VERSION 5.7 ;
  NOWIREEXTENSIONATPIN ON ;
  DIVIDERCHAR "/" ;
  BUSBITCHARS "[]" ;
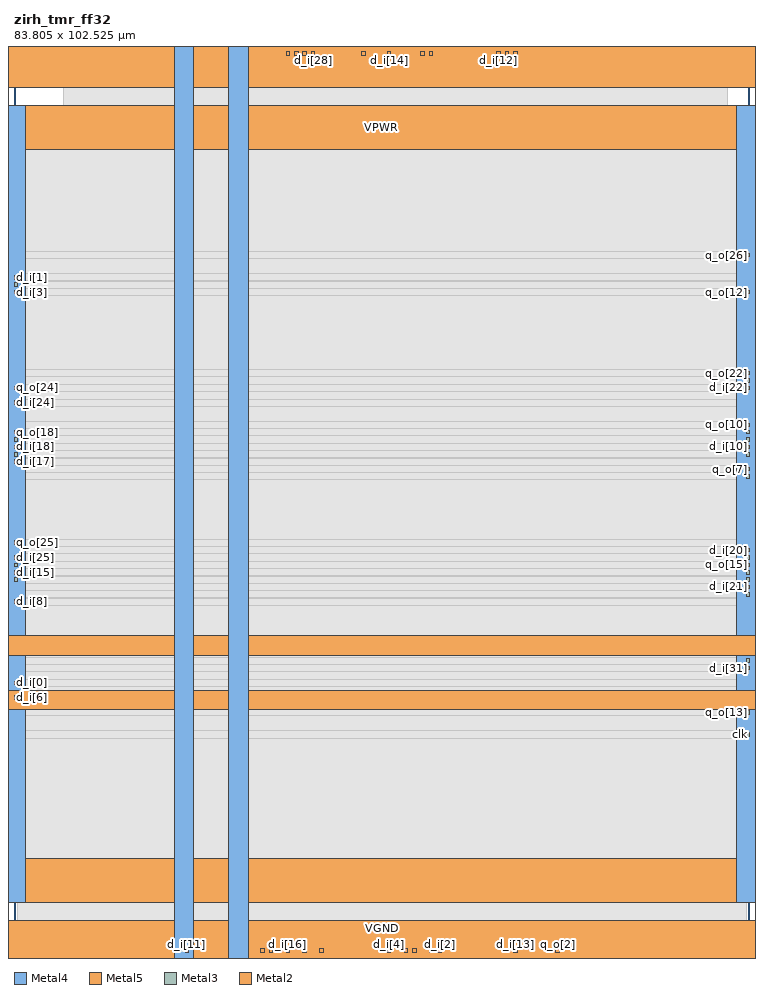
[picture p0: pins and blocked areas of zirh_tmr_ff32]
MACRO zirh_tmr_ff32
  CLASS BLOCK ;
  FOREIGN zirh_tmr_ff32 ;
  ORIGIN 0.000 0.000 ;
  SIZE 83.805 BY 102.525 ;
  PIN VGND
    DIRECTION INOUT ;
    USE GROUND ;
    PORT
      LAYER Metal4 ;
        RECT -10.740 -1.380 -5.740 103.440 ;
    END
    PORT
      LAYER Metal4 ;
        RECT 89.260 -1.380 94.260 103.440 ;
    END
    PORT
      LAYER Metal5 ;
        RECT -10.740 -1.380 94.260 3.620 ;
    END
    PORT
      LAYER Metal5 ;
        RECT -10.740 98.440 94.260 103.440 ;
    END
    PORT
      LAYER Metal4 ;
        RECT 24.460 -1.380 26.660 103.440 ;
    END
    PORT
      LAYER Metal5 ;
        RECT -10.740 33.820 94.260 36.020 ;
    END
  END VGND
  PIN VPWR
    DIRECTION INOUT ;
    USE POWER ;
    PORT
      LAYER Metal4 ;
        RECT -3.740 5.620 1.260 96.440 ;
    END
    PORT
      LAYER Metal4 ;
        RECT 82.260 5.620 87.260 96.440 ;
    END
    PORT
      LAYER Metal5 ;
        RECT -3.740 5.620 87.260 10.620 ;
    END
    PORT
      LAYER Metal5 ;
        RECT -3.740 91.440 87.260 96.440 ;
    END
    PORT
      LAYER Metal4 ;
        RECT 18.260 -1.380 20.460 103.440 ;
    END
    PORT
      LAYER Metal5 ;
        RECT -10.740 27.620 94.260 29.820 ;
    END
  END VPWR
  PIN clk
    DIRECTION INPUT ;
    USE SIGNAL ;
    ANTENNAGATEAREA 1.450800 ;
    PORT
      LAYER Metal3 ;
        RECT 83.405 24.580 83.805 24.980 ;
    END
  END clk
  PIN d_i[0]
    DIRECTION INPUT ;
    USE SIGNAL ;
    ANTENNAGATEAREA 0.180700 ;
    PORT
      LAYER Metal3 ;
        RECT 0.000 30.460 0.400 30.860 ;
    END
  END d_i[0]
  PIN d_i[10]
    DIRECTION INPUT ;
    USE SIGNAL ;
    ANTENNAGATEAREA 0.180700 ;
    PORT
      LAYER Metal3 ;
        RECT 83.405 57.340 83.805 57.740 ;
    END
  END d_i[10]
  PIN d_i[11]
    DIRECTION INPUT ;
    USE SIGNAL ;
    ANTENNAGATEAREA 0.180700 ;
    PORT
      LAYER Metal2 ;
        RECT 19.480 0.000 19.880 0.400 ;
    END
  END d_i[11]
  PIN d_i[12]
    DIRECTION INPUT ;
    USE SIGNAL ;
    ANTENNAGATEAREA 0.180700 ;
    PORT
      LAYER Metal2 ;
        RECT 55.000 102.125 55.400 102.525 ;
    END
  END d_i[12]
  PIN d_i[13]
    DIRECTION INPUT ;
    USE SIGNAL ;
    ANTENNAGATEAREA 0.180700 ;
    PORT
      LAYER Metal2 ;
        RECT 56.920 0.000 57.320 0.400 ;
    END
  END d_i[13]
  PIN d_i[14]
    DIRECTION INPUT ;
    USE SIGNAL ;
    ANTENNAGATEAREA 0.180700 ;
    PORT
      LAYER Metal2 ;
        RECT 42.520 102.125 42.920 102.525 ;
    END
  END d_i[14]
  PIN d_i[15]
    DIRECTION INPUT ;
    USE SIGNAL ;
    ANTENNAGATEAREA 0.180700 ;
    PORT
      LAYER Metal3 ;
        RECT 0.000 43.060 0.400 43.460 ;
    END
  END d_i[15]
  PIN d_i[16]
    DIRECTION INPUT ;
    USE SIGNAL ;
    ANTENNAGATEAREA 0.180700 ;
    PORT
      LAYER Metal2 ;
        RECT 31.000 0.000 31.400 0.400 ;
    END
  END d_i[16]
  PIN d_i[17]
    DIRECTION INPUT ;
    USE SIGNAL ;
    ANTENNAGATEAREA 0.180700 ;
    PORT
      LAYER Metal3 ;
        RECT 0.000 55.660 0.400 56.060 ;
    END
  END d_i[17]
  PIN d_i[18]
    DIRECTION INPUT ;
    USE SIGNAL ;
    ANTENNAGATEAREA 0.180700 ;
    PORT
      LAYER Metal3 ;
        RECT 0.000 57.340 0.400 57.740 ;
    END
  END d_i[18]
  PIN d_i[19]
    DIRECTION INPUT ;
    USE SIGNAL ;
    ANTENNAGATEAREA 0.180700 ;
    PORT
      LAYER Metal2 ;
        RECT 34.840 0.000 35.240 0.400 ;
    END
  END d_i[19]
  PIN d_i[1]
    DIRECTION INPUT ;
    USE SIGNAL ;
    ANTENNAGATEAREA 0.180700 ;
    PORT
      LAYER Metal3 ;
        RECT 0.000 76.660 0.400 77.060 ;
    END
  END d_i[1]
  PIN d_i[20]
    DIRECTION INPUT ;
    USE SIGNAL ;
    ANTENNAGATEAREA 0.180700 ;
    PORT
      LAYER Metal3 ;
        RECT 83.405 45.580 83.805 45.980 ;
    END
  END d_i[20]
  PIN d_i[21]
    DIRECTION INPUT ;
    USE SIGNAL ;
    ANTENNAGATEAREA 0.180700 ;
    PORT
      LAYER Metal3 ;
        RECT 83.405 41.380 83.805 41.780 ;
    END
  END d_i[21]
  PIN d_i[22]
    DIRECTION INPUT ;
    USE SIGNAL ;
    ANTENNAGATEAREA 0.180700 ;
    PORT
      LAYER Metal3 ;
        RECT 83.405 64.060 83.805 64.460 ;
    END
  END d_i[22]
  PIN d_i[23]
    DIRECTION INPUT ;
    USE SIGNAL ;
    ANTENNAGATEAREA 0.180700 ;
    PORT
      LAYER Metal2 ;
        RECT 39.640 102.125 40.040 102.525 ;
    END
  END d_i[23]
  PIN d_i[24]
    DIRECTION INPUT ;
    USE SIGNAL ;
    ANTENNAGATEAREA 0.180700 ;
    PORT
      LAYER Metal3 ;
        RECT 0.000 62.380 0.400 62.780 ;
    END
  END d_i[24]
  PIN d_i[25]
    DIRECTION INPUT ;
    USE SIGNAL ;
    ANTENNAGATEAREA 0.180700 ;
    PORT
      LAYER Metal3 ;
        RECT 0.000 44.740 0.400 45.140 ;
    END
  END d_i[25]
  PIN d_i[26]
    DIRECTION INPUT ;
    USE SIGNAL ;
    ANTENNAGATEAREA 0.180700 ;
    PORT
      LAYER Metal2 ;
        RECT 55.960 102.125 56.360 102.525 ;
    END
  END d_i[26]
  PIN d_i[27]
    DIRECTION INPUT ;
    USE SIGNAL ;
    ANTENNAGATEAREA 0.180700 ;
    PORT
      LAYER Metal3 ;
        RECT 0.000 42.220 0.400 42.620 ;
    END
  END d_i[27]
  PIN d_i[28]
    DIRECTION INPUT ;
    USE SIGNAL ;
    ANTENNAGATEAREA 0.180700 ;
    PORT
      LAYER Metal2 ;
        RECT 33.880 102.125 34.280 102.525 ;
    END
  END d_i[28]
  PIN d_i[29]
    DIRECTION INPUT ;
    USE SIGNAL ;
    ANTENNAGATEAREA 0.180700 ;
    PORT
      LAYER Metal3 ;
        RECT 0.000 56.500 0.400 56.900 ;
    END
  END d_i[29]
  PIN d_i[2]
    DIRECTION INPUT ;
    USE SIGNAL ;
    ANTENNAGATEAREA 0.180700 ;
    PORT
      LAYER Metal2 ;
        RECT 48.280 0.000 48.680 0.400 ;
    END
  END d_i[2]
  PIN d_i[30]
    DIRECTION INPUT ;
    USE SIGNAL ;
    ANTENNAGATEAREA 0.180700 ;
    PORT
      LAYER Metal3 ;
        RECT 83.405 40.540 83.805 40.940 ;
    END
  END d_i[30]
  PIN d_i[31]
    DIRECTION INPUT ;
    USE SIGNAL ;
    ANTENNAGATEAREA 0.180700 ;
    PORT
      LAYER Metal3 ;
        RECT 83.405 32.140 83.805 32.540 ;
    END
  END d_i[31]
  PIN d_i[3]
    DIRECTION INPUT ;
    USE SIGNAL ;
    ANTENNAGATEAREA 0.180700 ;
    PORT
      LAYER Metal3 ;
        RECT 0.000 74.980 0.400 75.380 ;
    END
  END d_i[3]
  PIN d_i[4]
    DIRECTION INPUT ;
    USE SIGNAL ;
    ANTENNAGATEAREA 0.180700 ;
    PORT
      LAYER Metal2 ;
        RECT 42.520 0.000 42.920 0.400 ;
    END
  END d_i[4]
  PIN d_i[5]
    DIRECTION INPUT ;
    USE SIGNAL ;
    ANTENNAGATEAREA 0.180700 ;
    PORT
      LAYER Metal3 ;
        RECT 83.405 56.500 83.805 56.900 ;
    END
  END d_i[5]
  PIN d_i[6]
    DIRECTION INPUT ;
    USE SIGNAL ;
    ANTENNAGATEAREA 0.180700 ;
    PORT
      LAYER Metal3 ;
        RECT 0.000 28.780 0.400 29.180 ;
    END
  END d_i[6]
  PIN d_i[7]
    DIRECTION INPUT ;
    USE SIGNAL ;
    ANTENNAGATEAREA 0.180700 ;
    PORT
      LAYER Metal3 ;
        RECT 83.405 53.980 83.805 54.380 ;
    END
  END d_i[7]
  PIN d_i[8]
    DIRECTION INPUT ;
    USE SIGNAL ;
    ANTENNAGATEAREA 0.180700 ;
    PORT
      LAYER Metal3 ;
        RECT 0.000 39.700 0.400 40.100 ;
    END
  END d_i[8]
  PIN d_i[9]
    DIRECTION INPUT ;
    USE SIGNAL ;
    ANTENNAGATEAREA 0.180700 ;
    PORT
      LAYER Metal2 ;
        RECT 32.920 102.125 33.320 102.525 ;
    END
  END d_i[9]
  PIN q_o[0]
    DIRECTION OUTPUT ;
    USE SIGNAL ;
    ANTENNADIFFAREA 0.708600 ;
    PORT
      LAYER Metal2 ;
        RECT 28.120 0.000 28.520 0.400 ;
    END
  END q_o[0]
  PIN q_o[10]
    DIRECTION OUTPUT ;
    USE SIGNAL ;
    ANTENNADIFFAREA 0.708600 ;
    PORT
      LAYER Metal3 ;
        RECT 83.405 59.860 83.805 60.260 ;
    END
  END q_o[10]
  PIN q_o[11]
    DIRECTION OUTPUT ;
    USE SIGNAL ;
    ANTENNADIFFAREA 0.708600 ;
    PORT
      LAYER Metal2 ;
        RECT 32.920 0.000 33.320 0.400 ;
    END
  END q_o[11]
  PIN q_o[12]
    DIRECTION OUTPUT ;
    USE SIGNAL ;
    ANTENNADIFFAREA 0.708600 ;
    PORT
      LAYER Metal3 ;
        RECT 83.405 74.980 83.805 75.380 ;
    END
  END q_o[12]
  PIN q_o[13]
    DIRECTION OUTPUT ;
    USE SIGNAL ;
    ANTENNADIFFAREA 0.708600 ;
    PORT
      LAYER Metal3 ;
        RECT 83.405 27.100 83.805 27.500 ;
    END
  END q_o[13]
  PIN q_o[14]
    DIRECTION OUTPUT ;
    USE SIGNAL ;
    ANTENNADIFFAREA 0.708600 ;
    PORT
      LAYER Metal2 ;
        RECT 56.920 102.125 57.320 102.525 ;
    END
  END q_o[14]
  PIN q_o[15]
    DIRECTION OUTPUT ;
    USE SIGNAL ;
    ANTENNADIFFAREA 0.708600 ;
    PORT
      LAYER Metal3 ;
        RECT 83.405 43.900 83.805 44.300 ;
    END
  END q_o[15]
  PIN q_o[16]
    DIRECTION OUTPUT ;
    USE SIGNAL ;
    ANTENNADIFFAREA 0.708600 ;
    PORT
      LAYER Metal2 ;
        RECT 45.400 0.000 45.800 0.400 ;
    END
  END q_o[16]
  PIN q_o[17]
    DIRECTION OUTPUT ;
    USE SIGNAL ;
    ANTENNADIFFAREA 0.708600 ;
    PORT
      LAYER Metal3 ;
        RECT 83.405 59.020 83.805 59.420 ;
    END
  END q_o[17]
  PIN q_o[18]
    DIRECTION OUTPUT ;
    USE SIGNAL ;
    ANTENNADIFFAREA 0.708600 ;
    PORT
      LAYER Metal3 ;
        RECT 0.000 59.020 0.400 59.420 ;
    END
  END q_o[18]
  PIN q_o[19]
    DIRECTION OUTPUT ;
    USE SIGNAL ;
    ANTENNADIFFAREA 0.708600 ;
    PORT
      LAYER Metal2 ;
        RECT 47.320 0.000 47.720 0.400 ;
    END
  END q_o[19]
  PIN q_o[1]
    DIRECTION OUTPUT ;
    USE SIGNAL ;
    ANTENNADIFFAREA 0.708600 ;
    PORT
      LAYER Metal2 ;
        RECT 31.960 102.125 32.360 102.525 ;
    END
  END q_o[1]
  PIN q_o[20]
    DIRECTION OUTPUT ;
    USE SIGNAL ;
    ANTENNADIFFAREA 0.708600 ;
    PORT
      LAYER Metal3 ;
        RECT 83.405 44.740 83.805 45.140 ;
    END
  END q_o[20]
  PIN q_o[21]
    DIRECTION OUTPUT ;
    USE SIGNAL ;
    ANTENNADIFFAREA 0.708600 ;
    PORT
      LAYER Metal3 ;
        RECT 83.405 43.060 83.805 43.460 ;
    END
  END q_o[21]
  PIN q_o[22]
    DIRECTION OUTPUT ;
    USE SIGNAL ;
    ANTENNADIFFAREA 0.708600 ;
    PORT
      LAYER Metal3 ;
        RECT 83.405 65.740 83.805 66.140 ;
    END
  END q_o[22]
  PIN q_o[23]
    DIRECTION OUTPUT ;
    USE SIGNAL ;
    ANTENNADIFFAREA 0.708600 ;
    PORT
      LAYER Metal3 ;
        RECT 83.405 64.900 83.805 65.300 ;
    END
  END q_o[23]
  PIN q_o[24]
    DIRECTION OUTPUT ;
    USE SIGNAL ;
    ANTENNADIFFAREA 0.708600 ;
    PORT
      LAYER Metal3 ;
        RECT 0.000 64.060 0.400 64.460 ;
    END
  END q_o[24]
  PIN q_o[25]
    DIRECTION OUTPUT ;
    USE SIGNAL ;
    ANTENNADIFFAREA 0.708600 ;
    PORT
      LAYER Metal3 ;
        RECT 0.000 46.420 0.400 46.820 ;
    END
  END q_o[25]
  PIN q_o[26]
    DIRECTION OUTPUT ;
    USE SIGNAL ;
    ANTENNADIFFAREA 0.708600 ;
    PORT
      LAYER Metal3 ;
        RECT 83.405 79.180 83.805 79.580 ;
    END
  END q_o[26]
  PIN q_o[27]
    DIRECTION OUTPUT ;
    USE SIGNAL ;
    ANTENNADIFFAREA 0.708600 ;
    PORT
      LAYER Metal3 ;
        RECT 0.000 43.900 0.400 44.300 ;
    END
  END q_o[27]
  PIN q_o[28]
    DIRECTION OUTPUT ;
    USE SIGNAL ;
    ANTENNADIFFAREA 0.708600 ;
    PORT
      LAYER Metal2 ;
        RECT 47.320 102.125 47.720 102.525 ;
    END
  END q_o[28]
  PIN q_o[29]
    DIRECTION OUTPUT ;
    USE SIGNAL ;
    ANTENNADIFFAREA 0.708600 ;
    PORT
      LAYER Metal3 ;
        RECT 0.000 58.180 0.400 58.580 ;
    END
  END q_o[29]
  PIN q_o[2]
    DIRECTION OUTPUT ;
    USE SIGNAL ;
    ANTENNADIFFAREA 0.708600 ;
    PORT
      LAYER Metal2 ;
        RECT 61.720 0.000 62.120 0.400 ;
    END
  END q_o[2]
  PIN q_o[30]
    DIRECTION OUTPUT ;
    USE SIGNAL ;
    ANTENNADIFFAREA 0.708600 ;
    PORT
      LAYER Metal3 ;
        RECT 83.405 42.220 83.805 42.620 ;
    END
  END q_o[30]
  PIN q_o[31]
    DIRECTION OUTPUT ;
    USE SIGNAL ;
    ANTENNADIFFAREA 0.708600 ;
    PORT
      LAYER Metal3 ;
        RECT 83.405 32.980 83.805 33.380 ;
    END
  END q_o[31]
  PIN q_o[3]
    DIRECTION OUTPUT ;
    USE SIGNAL ;
    ANTENNADIFFAREA 0.708600 ;
    PORT
      LAYER Metal2 ;
        RECT 31.000 102.125 31.400 102.525 ;
    END
  END q_o[3]
  PIN q_o[4]
    DIRECTION OUTPUT ;
    USE SIGNAL ;
    ANTENNADIFFAREA 0.708600 ;
    PORT
      LAYER Metal2 ;
        RECT 55.960 0.000 56.360 0.400 ;
    END
  END q_o[4]
  PIN q_o[5]
    DIRECTION OUTPUT ;
    USE SIGNAL ;
    ANTENNADIFFAREA 0.708600 ;
    PORT
      LAYER Metal3 ;
        RECT 83.405 58.180 83.805 58.580 ;
    END
  END q_o[5]
  PIN q_o[6]
    DIRECTION OUTPUT ;
    USE SIGNAL ;
    ANTENNADIFFAREA 0.708600 ;
    PORT
      LAYER Metal2 ;
        RECT 29.080 0.000 29.480 0.400 ;
    END
  END q_o[6]
  PIN q_o[7]
    DIRECTION OUTPUT ;
    USE SIGNAL ;
    ANTENNADIFFAREA 0.708600 ;
    PORT
      LAYER Metal3 ;
        RECT 83.405 54.820 83.805 55.220 ;
    END
  END q_o[7]
  PIN q_o[8]
    DIRECTION OUTPUT ;
    USE SIGNAL ;
    ANTENNADIFFAREA 0.708600 ;
    PORT
      LAYER Metal2 ;
        RECT 44.440 0.000 44.840 0.400 ;
    END
  END q_o[8]
  PIN q_o[9]
    DIRECTION OUTPUT ;
    USE SIGNAL ;
    ANTENNADIFFAREA 0.708600 ;
    PORT
      LAYER Metal2 ;
        RECT 46.360 102.125 46.760 102.525 ;
    END
  END q_o[9]
  PIN rst_n
    DIRECTION INPUT ;
    USE SIGNAL ;
    ANTENNAGATEAREA 0.180700 ;
    PORT
      LAYER Metal3 ;
        RECT 0.000 75.820 0.400 76.220 ;
    END
  END rst_n
  OBS
      LAYER GatPoly ;
        RECT 5.760 14.970 77.760 87.090 ;
      LAYER Metal1 ;
        RECT 5.760 14.900 77.760 87.160 ;
      LAYER Metal2 ;
        RECT 5.655 101.915 30.790 102.125 ;
        RECT 31.610 101.915 31.750 102.125 ;
        RECT 32.570 101.915 32.710 102.125 ;
        RECT 33.530 101.915 33.670 102.125 ;
        RECT 34.490 101.915 39.430 102.125 ;
        RECT 40.250 101.915 42.310 102.125 ;
        RECT 43.130 101.915 46.150 102.125 ;
        RECT 46.970 101.915 47.110 102.125 ;
        RECT 47.930 101.915 54.790 102.125 ;
        RECT 55.610 101.915 55.750 102.125 ;
        RECT 56.570 101.915 56.710 102.125 ;
        RECT 57.530 101.915 81.225 102.125 ;
        RECT 5.655 0.610 81.225 101.915 ;
        RECT 5.655 0.100 19.270 0.610 ;
        RECT 20.090 0.100 27.910 0.610 ;
        RECT 28.730 0.100 28.870 0.610 ;
        RECT 29.690 0.100 30.790 0.610 ;
        RECT 31.610 0.100 32.710 0.610 ;
        RECT 33.530 0.100 34.630 0.610 ;
        RECT 35.450 0.100 42.310 0.610 ;
        RECT 43.130 0.100 44.230 0.610 ;
        RECT 45.050 0.100 45.190 0.610 ;
        RECT 46.010 0.100 47.110 0.610 ;
        RECT 47.930 0.100 48.070 0.610 ;
        RECT 48.890 0.100 55.750 0.610 ;
        RECT 56.570 0.100 56.710 0.610 ;
        RECT 57.530 0.100 61.510 0.610 ;
        RECT 62.330 0.100 81.225 0.610 ;
      LAYER Metal3 ;
        RECT 0.400 79.790 83.405 94.600 ;
        RECT 0.400 78.970 83.195 79.790 ;
        RECT 0.400 77.270 83.405 78.970 ;
        RECT 0.610 76.450 83.405 77.270 ;
        RECT 0.400 76.430 83.405 76.450 ;
        RECT 0.610 75.610 83.405 76.430 ;
        RECT 0.400 75.590 83.405 75.610 ;
        RECT 0.610 74.770 83.195 75.590 ;
        RECT 0.400 66.350 83.405 74.770 ;
        RECT 0.400 65.530 83.195 66.350 ;
        RECT 0.400 65.510 83.405 65.530 ;
        RECT 0.400 64.690 83.195 65.510 ;
        RECT 0.400 64.670 83.405 64.690 ;
        RECT 0.610 63.850 83.195 64.670 ;
        RECT 0.400 62.990 83.405 63.850 ;
        RECT 0.610 62.170 83.405 62.990 ;
        RECT 0.400 60.470 83.405 62.170 ;
        RECT 0.400 59.650 83.195 60.470 ;
        RECT 0.400 59.630 83.405 59.650 ;
        RECT 0.610 58.810 83.195 59.630 ;
        RECT 0.400 58.790 83.405 58.810 ;
        RECT 0.610 57.970 83.195 58.790 ;
        RECT 0.400 57.950 83.405 57.970 ;
        RECT 0.610 57.130 83.195 57.950 ;
        RECT 0.400 57.110 83.405 57.130 ;
        RECT 0.610 56.290 83.195 57.110 ;
        RECT 0.400 56.270 83.405 56.290 ;
        RECT 0.610 55.450 83.405 56.270 ;
        RECT 0.400 55.430 83.405 55.450 ;
        RECT 0.400 54.610 83.195 55.430 ;
        RECT 0.400 54.590 83.405 54.610 ;
        RECT 0.400 53.770 83.195 54.590 ;
        RECT 0.400 47.030 83.405 53.770 ;
        RECT 0.610 46.210 83.405 47.030 ;
        RECT 0.400 46.190 83.405 46.210 ;
        RECT 0.400 45.370 83.195 46.190 ;
        RECT 0.400 45.350 83.405 45.370 ;
        RECT 0.610 44.530 83.195 45.350 ;
        RECT 0.400 44.510 83.405 44.530 ;
        RECT 0.610 43.690 83.195 44.510 ;
        RECT 0.400 43.670 83.405 43.690 ;
        RECT 0.610 42.850 83.195 43.670 ;
        RECT 0.400 42.830 83.405 42.850 ;
        RECT 0.610 42.010 83.195 42.830 ;
        RECT 0.400 41.990 83.405 42.010 ;
        RECT 0.400 41.170 83.195 41.990 ;
        RECT 0.400 41.150 83.405 41.170 ;
        RECT 0.400 40.330 83.195 41.150 ;
        RECT 0.400 40.310 83.405 40.330 ;
        RECT 0.610 39.490 83.405 40.310 ;
        RECT 0.400 33.590 83.405 39.490 ;
        RECT 0.400 32.770 83.195 33.590 ;
        RECT 0.400 32.750 83.405 32.770 ;
        RECT 0.400 31.930 83.195 32.750 ;
        RECT 0.400 31.070 83.405 31.930 ;
        RECT 0.610 30.250 83.405 31.070 ;
        RECT 0.400 29.390 83.405 30.250 ;
        RECT 0.610 28.570 83.405 29.390 ;
        RECT 0.400 27.710 83.405 28.570 ;
        RECT 0.400 26.890 83.195 27.710 ;
        RECT 0.400 25.190 83.405 26.890 ;
        RECT 0.400 24.370 83.195 25.190 ;
        RECT 0.400 0.320 83.405 24.370 ;
  END
END zirh_tmr_ff32
END LIBRARY

